# Generated by FakeRAM 2.0
VERSION 5.7 ;
BUSBITCHARS "[]" ;
PROPERTYDEFINITIONS
  MACRO width INTEGER ;
  MACRO depth INTEGER ;
  MACRO banks INTEGER ;
END PROPERTYDEFINITIONS
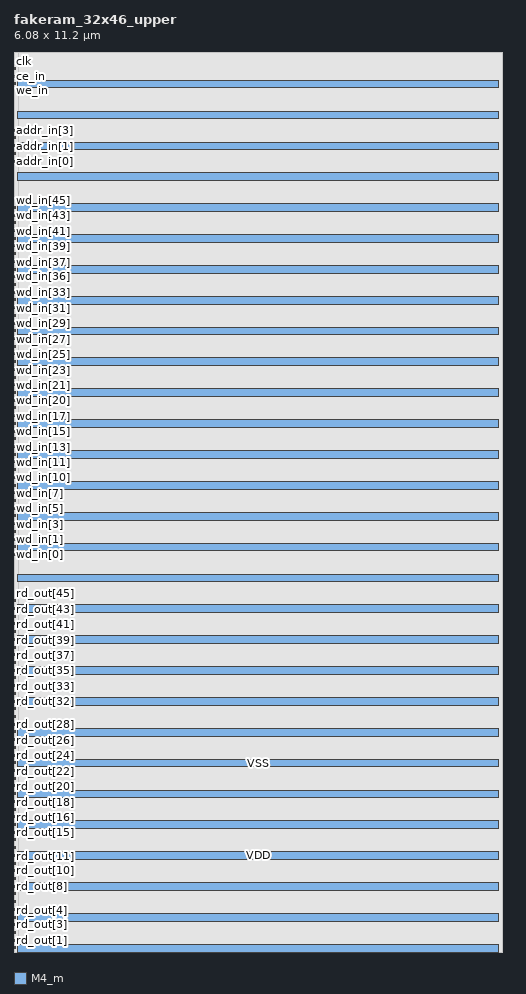
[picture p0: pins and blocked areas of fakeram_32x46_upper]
MACRO fakeram_32x46_upper
  PROPERTY width 46 ;
  PROPERTY depth 32 ;
  PROPERTY banks 1 ;
  FOREIGN fakeram_32x46_upper 0 0 ;
  SYMMETRY X Y R90 ;
  SIZE 6.080 BY 11.200 ;
  CLASS BLOCK ;
  PIN rd_out[0]
    DIRECTION OUTPUT ;
    USE SIGNAL ;
    SHAPE ABUTMENT ;
    PORT
      LAYER M4_m ;
      RECT 0.000 0.039 0.024 0.063 ;
    END
  END rd_out[0]
  PIN rd_out[1]
    DIRECTION OUTPUT ;
    USE SIGNAL ;
    SHAPE ABUTMENT ;
    PORT
      LAYER M4_m ;
      RECT 0.000 0.135 0.024 0.159 ;
    END
  END rd_out[1]
  PIN rd_out[2]
    DIRECTION OUTPUT ;
    USE SIGNAL ;
    SHAPE ABUTMENT ;
    PORT
      LAYER M4_m ;
      RECT 0.000 0.231 0.024 0.255 ;
    END
  END rd_out[2]
  PIN rd_out[3]
    DIRECTION OUTPUT ;
    USE SIGNAL ;
    SHAPE ABUTMENT ;
    PORT
      LAYER M4_m ;
      RECT 0.000 0.327 0.024 0.351 ;
    END
  END rd_out[3]
  PIN rd_out[4]
    DIRECTION OUTPUT ;
    USE SIGNAL ;
    SHAPE ABUTMENT ;
    PORT
      LAYER M4_m ;
      RECT 0.000 0.423 0.024 0.447 ;
    END
  END rd_out[4]
  PIN rd_out[5]
    DIRECTION OUTPUT ;
    USE SIGNAL ;
    SHAPE ABUTMENT ;
    PORT
      LAYER M4_m ;
      RECT 0.000 0.519 0.024 0.543 ;
    END
  END rd_out[5]
  PIN rd_out[6]
    DIRECTION OUTPUT ;
    USE SIGNAL ;
    SHAPE ABUTMENT ;
    PORT
      LAYER M4_m ;
      RECT 0.000 0.615 0.024 0.639 ;
    END
  END rd_out[6]
  PIN rd_out[7]
    DIRECTION OUTPUT ;
    USE SIGNAL ;
    SHAPE ABUTMENT ;
    PORT
      LAYER M4_m ;
      RECT 0.000 0.711 0.024 0.735 ;
    END
  END rd_out[7]
  PIN rd_out[8]
    DIRECTION OUTPUT ;
    USE SIGNAL ;
    SHAPE ABUTMENT ;
    PORT
      LAYER M4_m ;
      RECT 0.000 0.807 0.024 0.831 ;
    END
  END rd_out[8]
  PIN rd_out[9]
    DIRECTION OUTPUT ;
    USE SIGNAL ;
    SHAPE ABUTMENT ;
    PORT
      LAYER M4_m ;
      RECT 0.000 0.903 0.024 0.927 ;
    END
  END rd_out[9]
  PIN rd_out[10]
    DIRECTION OUTPUT ;
    USE SIGNAL ;
    SHAPE ABUTMENT ;
    PORT
      LAYER M4_m ;
      RECT 0.000 0.999 0.024 1.023 ;
    END
  END rd_out[10]
  PIN rd_out[11]
    DIRECTION OUTPUT ;
    USE SIGNAL ;
    SHAPE ABUTMENT ;
    PORT
      LAYER M4_m ;
      RECT 0.000 1.095 0.024 1.119 ;
    END
  END rd_out[11]
  PIN rd_out[12]
    DIRECTION OUTPUT ;
    USE SIGNAL ;
    SHAPE ABUTMENT ;
    PORT
      LAYER M4_m ;
      RECT 0.000 1.191 0.024 1.215 ;
    END
  END rd_out[12]
  PIN rd_out[13]
    DIRECTION OUTPUT ;
    USE SIGNAL ;
    SHAPE ABUTMENT ;
    PORT
      LAYER M4_m ;
      RECT 0.000 1.287 0.024 1.311 ;
    END
  END rd_out[13]
  PIN rd_out[14]
    DIRECTION OUTPUT ;
    USE SIGNAL ;
    SHAPE ABUTMENT ;
    PORT
      LAYER M4_m ;
      RECT 0.000 1.383 0.024 1.407 ;
    END
  END rd_out[14]
  PIN rd_out[15]
    DIRECTION OUTPUT ;
    USE SIGNAL ;
    SHAPE ABUTMENT ;
    PORT
      LAYER M4_m ;
      RECT 0.000 1.479 0.024 1.503 ;
    END
  END rd_out[15]
  PIN rd_out[16]
    DIRECTION OUTPUT ;
    USE SIGNAL ;
    SHAPE ABUTMENT ;
    PORT
      LAYER M4_m ;
      RECT 0.000 1.575 0.024 1.599 ;
    END
  END rd_out[16]
  PIN rd_out[17]
    DIRECTION OUTPUT ;
    USE SIGNAL ;
    SHAPE ABUTMENT ;
    PORT
      LAYER M4_m ;
      RECT 0.000 1.671 0.024 1.695 ;
    END
  END rd_out[17]
  PIN rd_out[18]
    DIRECTION OUTPUT ;
    USE SIGNAL ;
    SHAPE ABUTMENT ;
    PORT
      LAYER M4_m ;
      RECT 0.000 1.767 0.024 1.791 ;
    END
  END rd_out[18]
  PIN rd_out[19]
    DIRECTION OUTPUT ;
    USE SIGNAL ;
    SHAPE ABUTMENT ;
    PORT
      LAYER M4_m ;
      RECT 0.000 1.863 0.024 1.887 ;
    END
  END rd_out[19]
  PIN rd_out[20]
    DIRECTION OUTPUT ;
    USE SIGNAL ;
    SHAPE ABUTMENT ;
    PORT
      LAYER M4_m ;
      RECT 0.000 1.959 0.024 1.983 ;
    END
  END rd_out[20]
  PIN rd_out[21]
    DIRECTION OUTPUT ;
    USE SIGNAL ;
    SHAPE ABUTMENT ;
    PORT
      LAYER M4_m ;
      RECT 0.000 2.055 0.024 2.079 ;
    END
  END rd_out[21]
  PIN rd_out[22]
    DIRECTION OUTPUT ;
    USE SIGNAL ;
    SHAPE ABUTMENT ;
    PORT
      LAYER M4_m ;
      RECT 0.000 2.151 0.024 2.175 ;
    END
  END rd_out[22]
  PIN rd_out[23]
    DIRECTION OUTPUT ;
    USE SIGNAL ;
    SHAPE ABUTMENT ;
    PORT
      LAYER M4_m ;
      RECT 0.000 2.247 0.024 2.271 ;
    END
  END rd_out[23]
  PIN rd_out[24]
    DIRECTION OUTPUT ;
    USE SIGNAL ;
    SHAPE ABUTMENT ;
    PORT
      LAYER M4_m ;
      RECT 0.000 2.343 0.024 2.367 ;
    END
  END rd_out[24]
  PIN rd_out[25]
    DIRECTION OUTPUT ;
    USE SIGNAL ;
    SHAPE ABUTMENT ;
    PORT
      LAYER M4_m ;
      RECT 0.000 2.439 0.024 2.463 ;
    END
  END rd_out[25]
  PIN rd_out[26]
    DIRECTION OUTPUT ;
    USE SIGNAL ;
    SHAPE ABUTMENT ;
    PORT
      LAYER M4_m ;
      RECT 0.000 2.535 0.024 2.559 ;
    END
  END rd_out[26]
  PIN rd_out[27]
    DIRECTION OUTPUT ;
    USE SIGNAL ;
    SHAPE ABUTMENT ;
    PORT
      LAYER M4_m ;
      RECT 0.000 2.631 0.024 2.655 ;
    END
  END rd_out[27]
  PIN rd_out[28]
    DIRECTION OUTPUT ;
    USE SIGNAL ;
    SHAPE ABUTMENT ;
    PORT
      LAYER M4_m ;
      RECT 0.000 2.727 0.024 2.751 ;
    END
  END rd_out[28]
  PIN rd_out[29]
    DIRECTION OUTPUT ;
    USE SIGNAL ;
    SHAPE ABUTMENT ;
    PORT
      LAYER M4_m ;
      RECT 0.000 2.823 0.024 2.847 ;
    END
  END rd_out[29]
  PIN rd_out[30]
    DIRECTION OUTPUT ;
    USE SIGNAL ;
    SHAPE ABUTMENT ;
    PORT
      LAYER M4_m ;
      RECT 0.000 2.919 0.024 2.943 ;
    END
  END rd_out[30]
  PIN rd_out[31]
    DIRECTION OUTPUT ;
    USE SIGNAL ;
    SHAPE ABUTMENT ;
    PORT
      LAYER M4_m ;
      RECT 0.000 3.015 0.024 3.039 ;
    END
  END rd_out[31]
  PIN rd_out[32]
    DIRECTION OUTPUT ;
    USE SIGNAL ;
    SHAPE ABUTMENT ;
    PORT
      LAYER M4_m ;
      RECT 0.000 3.111 0.024 3.135 ;
    END
  END rd_out[32]
  PIN rd_out[33]
    DIRECTION OUTPUT ;
    USE SIGNAL ;
    SHAPE ABUTMENT ;
    PORT
      LAYER M4_m ;
      RECT 0.000 3.207 0.024 3.231 ;
    END
  END rd_out[33]
  PIN rd_out[34]
    DIRECTION OUTPUT ;
    USE SIGNAL ;
    SHAPE ABUTMENT ;
    PORT
      LAYER M4_m ;
      RECT 0.000 3.303 0.024 3.327 ;
    END
  END rd_out[34]
  PIN rd_out[35]
    DIRECTION OUTPUT ;
    USE SIGNAL ;
    SHAPE ABUTMENT ;
    PORT
      LAYER M4_m ;
      RECT 0.000 3.399 0.024 3.423 ;
    END
  END rd_out[35]
  PIN rd_out[36]
    DIRECTION OUTPUT ;
    USE SIGNAL ;
    SHAPE ABUTMENT ;
    PORT
      LAYER M4_m ;
      RECT 0.000 3.495 0.024 3.519 ;
    END
  END rd_out[36]
  PIN rd_out[37]
    DIRECTION OUTPUT ;
    USE SIGNAL ;
    SHAPE ABUTMENT ;
    PORT
      LAYER M4_m ;
      RECT 0.000 3.591 0.024 3.615 ;
    END
  END rd_out[37]
  PIN rd_out[38]
    DIRECTION OUTPUT ;
    USE SIGNAL ;
    SHAPE ABUTMENT ;
    PORT
      LAYER M4_m ;
      RECT 0.000 3.687 0.024 3.711 ;
    END
  END rd_out[38]
  PIN rd_out[39]
    DIRECTION OUTPUT ;
    USE SIGNAL ;
    SHAPE ABUTMENT ;
    PORT
      LAYER M4_m ;
      RECT 0.000 3.783 0.024 3.807 ;
    END
  END rd_out[39]
  PIN rd_out[40]
    DIRECTION OUTPUT ;
    USE SIGNAL ;
    SHAPE ABUTMENT ;
    PORT
      LAYER M4_m ;
      RECT 0.000 3.879 0.024 3.903 ;
    END
  END rd_out[40]
  PIN rd_out[41]
    DIRECTION OUTPUT ;
    USE SIGNAL ;
    SHAPE ABUTMENT ;
    PORT
      LAYER M4_m ;
      RECT 0.000 3.975 0.024 3.999 ;
    END
  END rd_out[41]
  PIN rd_out[42]
    DIRECTION OUTPUT ;
    USE SIGNAL ;
    SHAPE ABUTMENT ;
    PORT
      LAYER M4_m ;
      RECT 0.000 4.071 0.024 4.095 ;
    END
  END rd_out[42]
  PIN rd_out[43]
    DIRECTION OUTPUT ;
    USE SIGNAL ;
    SHAPE ABUTMENT ;
    PORT
      LAYER M4_m ;
      RECT 0.000 4.167 0.024 4.191 ;
    END
  END rd_out[43]
  PIN rd_out[44]
    DIRECTION OUTPUT ;
    USE SIGNAL ;
    SHAPE ABUTMENT ;
    PORT
      LAYER M4_m ;
      RECT 0.000 4.263 0.024 4.287 ;
    END
  END rd_out[44]
  PIN rd_out[45]
    DIRECTION OUTPUT ;
    USE SIGNAL ;
    SHAPE ABUTMENT ;
    PORT
      LAYER M4_m ;
      RECT 0.000 4.359 0.024 4.383 ;
    END
  END rd_out[45]
  PIN wd_in[0]
    DIRECTION INPUT ;
    USE SIGNAL ;
    SHAPE ABUTMENT ;
    PORT
      LAYER M4_m ;
      RECT 0.000 4.935 0.024 4.959 ;
    END
  END wd_in[0]
  PIN wd_in[1]
    DIRECTION INPUT ;
    USE SIGNAL ;
    SHAPE ABUTMENT ;
    PORT
      LAYER M4_m ;
      RECT 0.000 5.031 0.024 5.055 ;
    END
  END wd_in[1]
  PIN wd_in[2]
    DIRECTION INPUT ;
    USE SIGNAL ;
    SHAPE ABUTMENT ;
    PORT
      LAYER M4_m ;
      RECT 0.000 5.127 0.024 5.151 ;
    END
  END wd_in[2]
  PIN wd_in[3]
    DIRECTION INPUT ;
    USE SIGNAL ;
    SHAPE ABUTMENT ;
    PORT
      LAYER M4_m ;
      RECT 0.000 5.223 0.024 5.247 ;
    END
  END wd_in[3]
  PIN wd_in[4]
    DIRECTION INPUT ;
    USE SIGNAL ;
    SHAPE ABUTMENT ;
    PORT
      LAYER M4_m ;
      RECT 0.000 5.319 0.024 5.343 ;
    END
  END wd_in[4]
  PIN wd_in[5]
    DIRECTION INPUT ;
    USE SIGNAL ;
    SHAPE ABUTMENT ;
    PORT
      LAYER M4_m ;
      RECT 0.000 5.415 0.024 5.439 ;
    END
  END wd_in[5]
  PIN wd_in[6]
    DIRECTION INPUT ;
    USE SIGNAL ;
    SHAPE ABUTMENT ;
    PORT
      LAYER M4_m ;
      RECT 0.000 5.511 0.024 5.535 ;
    END
  END wd_in[6]
  PIN wd_in[7]
    DIRECTION INPUT ;
    USE SIGNAL ;
    SHAPE ABUTMENT ;
    PORT
      LAYER M4_m ;
      RECT 0.000 5.607 0.024 5.631 ;
    END
  END wd_in[7]
  PIN wd_in[8]
    DIRECTION INPUT ;
    USE SIGNAL ;
    SHAPE ABUTMENT ;
    PORT
      LAYER M4_m ;
      RECT 0.000 5.703 0.024 5.727 ;
    END
  END wd_in[8]
  PIN wd_in[9]
    DIRECTION INPUT ;
    USE SIGNAL ;
    SHAPE ABUTMENT ;
    PORT
      LAYER M4_m ;
      RECT 0.000 5.799 0.024 5.823 ;
    END
  END wd_in[9]
  PIN wd_in[10]
    DIRECTION INPUT ;
    USE SIGNAL ;
    SHAPE ABUTMENT ;
    PORT
      LAYER M4_m ;
      RECT 0.000 5.895 0.024 5.919 ;
    END
  END wd_in[10]
  PIN wd_in[11]
    DIRECTION INPUT ;
    USE SIGNAL ;
    SHAPE ABUTMENT ;
    PORT
      LAYER M4_m ;
      RECT 0.000 5.991 0.024 6.015 ;
    END
  END wd_in[11]
  PIN wd_in[12]
    DIRECTION INPUT ;
    USE SIGNAL ;
    SHAPE ABUTMENT ;
    PORT
      LAYER M4_m ;
      RECT 0.000 6.087 0.024 6.111 ;
    END
  END wd_in[12]
  PIN wd_in[13]
    DIRECTION INPUT ;
    USE SIGNAL ;
    SHAPE ABUTMENT ;
    PORT
      LAYER M4_m ;
      RECT 0.000 6.183 0.024 6.207 ;
    END
  END wd_in[13]
  PIN wd_in[14]
    DIRECTION INPUT ;
    USE SIGNAL ;
    SHAPE ABUTMENT ;
    PORT
      LAYER M4_m ;
      RECT 0.000 6.279 0.024 6.303 ;
    END
  END wd_in[14]
  PIN wd_in[15]
    DIRECTION INPUT ;
    USE SIGNAL ;
    SHAPE ABUTMENT ;
    PORT
      LAYER M4_m ;
      RECT 0.000 6.375 0.024 6.399 ;
    END
  END wd_in[15]
  PIN wd_in[16]
    DIRECTION INPUT ;
    USE SIGNAL ;
    SHAPE ABUTMENT ;
    PORT
      LAYER M4_m ;
      RECT 0.000 6.471 0.024 6.495 ;
    END
  END wd_in[16]
  PIN wd_in[17]
    DIRECTION INPUT ;
    USE SIGNAL ;
    SHAPE ABUTMENT ;
    PORT
      LAYER M4_m ;
      RECT 0.000 6.567 0.024 6.591 ;
    END
  END wd_in[17]
  PIN wd_in[18]
    DIRECTION INPUT ;
    USE SIGNAL ;
    SHAPE ABUTMENT ;
    PORT
      LAYER M4_m ;
      RECT 0.000 6.663 0.024 6.687 ;
    END
  END wd_in[18]
  PIN wd_in[19]
    DIRECTION INPUT ;
    USE SIGNAL ;
    SHAPE ABUTMENT ;
    PORT
      LAYER M4_m ;
      RECT 0.000 6.759 0.024 6.783 ;
    END
  END wd_in[19]
  PIN wd_in[20]
    DIRECTION INPUT ;
    USE SIGNAL ;
    SHAPE ABUTMENT ;
    PORT
      LAYER M4_m ;
      RECT 0.000 6.855 0.024 6.879 ;
    END
  END wd_in[20]
  PIN wd_in[21]
    DIRECTION INPUT ;
    USE SIGNAL ;
    SHAPE ABUTMENT ;
    PORT
      LAYER M4_m ;
      RECT 0.000 6.951 0.024 6.975 ;
    END
  END wd_in[21]
  PIN wd_in[22]
    DIRECTION INPUT ;
    USE SIGNAL ;
    SHAPE ABUTMENT ;
    PORT
      LAYER M4_m ;
      RECT 0.000 7.047 0.024 7.071 ;
    END
  END wd_in[22]
  PIN wd_in[23]
    DIRECTION INPUT ;
    USE SIGNAL ;
    SHAPE ABUTMENT ;
    PORT
      LAYER M4_m ;
      RECT 0.000 7.143 0.024 7.167 ;
    END
  END wd_in[23]
  PIN wd_in[24]
    DIRECTION INPUT ;
    USE SIGNAL ;
    SHAPE ABUTMENT ;
    PORT
      LAYER M4_m ;
      RECT 0.000 7.239 0.024 7.263 ;
    END
  END wd_in[24]
  PIN wd_in[25]
    DIRECTION INPUT ;
    USE SIGNAL ;
    SHAPE ABUTMENT ;
    PORT
      LAYER M4_m ;
      RECT 0.000 7.335 0.024 7.359 ;
    END
  END wd_in[25]
  PIN wd_in[26]
    DIRECTION INPUT ;
    USE SIGNAL ;
    SHAPE ABUTMENT ;
    PORT
      LAYER M4_m ;
      RECT 0.000 7.431 0.024 7.455 ;
    END
  END wd_in[26]
  PIN wd_in[27]
    DIRECTION INPUT ;
    USE SIGNAL ;
    SHAPE ABUTMENT ;
    PORT
      LAYER M4_m ;
      RECT 0.000 7.527 0.024 7.551 ;
    END
  END wd_in[27]
  PIN wd_in[28]
    DIRECTION INPUT ;
    USE SIGNAL ;
    SHAPE ABUTMENT ;
    PORT
      LAYER M4_m ;
      RECT 0.000 7.623 0.024 7.647 ;
    END
  END wd_in[28]
  PIN wd_in[29]
    DIRECTION INPUT ;
    USE SIGNAL ;
    SHAPE ABUTMENT ;
    PORT
      LAYER M4_m ;
      RECT 0.000 7.719 0.024 7.743 ;
    END
  END wd_in[29]
  PIN wd_in[30]
    DIRECTION INPUT ;
    USE SIGNAL ;
    SHAPE ABUTMENT ;
    PORT
      LAYER M4_m ;
      RECT 0.000 7.815 0.024 7.839 ;
    END
  END wd_in[30]
  PIN wd_in[31]
    DIRECTION INPUT ;
    USE SIGNAL ;
    SHAPE ABUTMENT ;
    PORT
      LAYER M4_m ;
      RECT 0.000 7.911 0.024 7.935 ;
    END
  END wd_in[31]
  PIN wd_in[32]
    DIRECTION INPUT ;
    USE SIGNAL ;
    SHAPE ABUTMENT ;
    PORT
      LAYER M4_m ;
      RECT 0.000 8.007 0.024 8.031 ;
    END
  END wd_in[32]
  PIN wd_in[33]
    DIRECTION INPUT ;
    USE SIGNAL ;
    SHAPE ABUTMENT ;
    PORT
      LAYER M4_m ;
      RECT 0.000 8.103 0.024 8.127 ;
    END
  END wd_in[33]
  PIN wd_in[34]
    DIRECTION INPUT ;
    USE SIGNAL ;
    SHAPE ABUTMENT ;
    PORT
      LAYER M4_m ;
      RECT 0.000 8.199 0.024 8.223 ;
    END
  END wd_in[34]
  PIN wd_in[35]
    DIRECTION INPUT ;
    USE SIGNAL ;
    SHAPE ABUTMENT ;
    PORT
      LAYER M4_m ;
      RECT 0.000 8.295 0.024 8.319 ;
    END
  END wd_in[35]
  PIN wd_in[36]
    DIRECTION INPUT ;
    USE SIGNAL ;
    SHAPE ABUTMENT ;
    PORT
      LAYER M4_m ;
      RECT 0.000 8.391 0.024 8.415 ;
    END
  END wd_in[36]
  PIN wd_in[37]
    DIRECTION INPUT ;
    USE SIGNAL ;
    SHAPE ABUTMENT ;
    PORT
      LAYER M4_m ;
      RECT 0.000 8.487 0.024 8.511 ;
    END
  END wd_in[37]
  PIN wd_in[38]
    DIRECTION INPUT ;
    USE SIGNAL ;
    SHAPE ABUTMENT ;
    PORT
      LAYER M4_m ;
      RECT 0.000 8.583 0.024 8.607 ;
    END
  END wd_in[38]
  PIN wd_in[39]
    DIRECTION INPUT ;
    USE SIGNAL ;
    SHAPE ABUTMENT ;
    PORT
      LAYER M4_m ;
      RECT 0.000 8.679 0.024 8.703 ;
    END
  END wd_in[39]
  PIN wd_in[40]
    DIRECTION INPUT ;
    USE SIGNAL ;
    SHAPE ABUTMENT ;
    PORT
      LAYER M4_m ;
      RECT 0.000 8.775 0.024 8.799 ;
    END
  END wd_in[40]
  PIN wd_in[41]
    DIRECTION INPUT ;
    USE SIGNAL ;
    SHAPE ABUTMENT ;
    PORT
      LAYER M4_m ;
      RECT 0.000 8.871 0.024 8.895 ;
    END
  END wd_in[41]
  PIN wd_in[42]
    DIRECTION INPUT ;
    USE SIGNAL ;
    SHAPE ABUTMENT ;
    PORT
      LAYER M4_m ;
      RECT 0.000 8.967 0.024 8.991 ;
    END
  END wd_in[42]
  PIN wd_in[43]
    DIRECTION INPUT ;
    USE SIGNAL ;
    SHAPE ABUTMENT ;
    PORT
      LAYER M4_m ;
      RECT 0.000 9.063 0.024 9.087 ;
    END
  END wd_in[43]
  PIN wd_in[44]
    DIRECTION INPUT ;
    USE SIGNAL ;
    SHAPE ABUTMENT ;
    PORT
      LAYER M4_m ;
      RECT 0.000 9.159 0.024 9.183 ;
    END
  END wd_in[44]
  PIN wd_in[45]
    DIRECTION INPUT ;
    USE SIGNAL ;
    SHAPE ABUTMENT ;
    PORT
      LAYER M4_m ;
      RECT 0.000 9.255 0.024 9.279 ;
    END
  END wd_in[45]
  PIN addr_in[0]
    DIRECTION INPUT ;
    USE SIGNAL ;
    SHAPE ABUTMENT ;
    PORT
      LAYER M4_m ;
      RECT 0.000 9.831 0.024 9.855 ;
    END
  END addr_in[0]
  PIN addr_in[1]
    DIRECTION INPUT ;
    USE SIGNAL ;
    SHAPE ABUTMENT ;
    PORT
      LAYER M4_m ;
      RECT 0.000 9.927 0.024 9.951 ;
    END
  END addr_in[1]
  PIN addr_in[2]
    DIRECTION INPUT ;
    USE SIGNAL ;
    SHAPE ABUTMENT ;
    PORT
      LAYER M4_m ;
      RECT 0.000 10.023 0.024 10.047 ;
    END
  END addr_in[2]
  PIN addr_in[3]
    DIRECTION INPUT ;
    USE SIGNAL ;
    SHAPE ABUTMENT ;
    PORT
      LAYER M4_m ;
      RECT 0.000 10.119 0.024 10.143 ;
    END
  END addr_in[3]
  PIN addr_in[4]
    DIRECTION INPUT ;
    USE SIGNAL ;
    SHAPE ABUTMENT ;
    PORT
      LAYER M4_m ;
      RECT 0.000 10.215 0.024 10.239 ;
    END
  END addr_in[4]
  PIN we_in
    DIRECTION INPUT ;
    USE SIGNAL ;
    SHAPE ABUTMENT ;
    PORT
      LAYER M4_m ;
      RECT 0.000 10.791 0.024 10.815 ;
    END
  END we_in
  PIN ce_in
    DIRECTION INPUT ;
    USE SIGNAL ;
    SHAPE ABUTMENT ;
    PORT
      LAYER M4_m ;
      RECT 0.000 10.887 0.024 10.911 ;
    END
  END ce_in
  PIN clk
    DIRECTION INPUT ;
    USE SIGNAL ;
    SHAPE ABUTMENT ;
    PORT
      LAYER M4_m ;
      RECT 0.000 10.983 0.024 11.007 ;
    END
  END clk
  PIN VSS
    DIRECTION INOUT ;
    USE GROUND ;
    PORT
      LAYER M4_m ;
      RECT 0.048 0.000 6.032 0.096 ;
      RECT 0.048 0.768 6.032 0.864 ;
      RECT 0.048 1.536 6.032 1.632 ;
      RECT 0.048 2.304 6.032 2.400 ;
      RECT 0.048 3.072 6.032 3.168 ;
      RECT 0.048 3.840 6.032 3.936 ;
      RECT 0.048 4.608 6.032 4.704 ;
      RECT 0.048 5.376 6.032 5.472 ;
      RECT 0.048 6.144 6.032 6.240 ;
      RECT 0.048 6.912 6.032 7.008 ;
      RECT 0.048 7.680 6.032 7.776 ;
      RECT 0.048 8.448 6.032 8.544 ;
      RECT 0.048 9.216 6.032 9.312 ;
      RECT 0.048 9.984 6.032 10.080 ;
      RECT 0.048 10.752 6.032 10.848 ;
    END
  END VSS
  PIN VDD
    DIRECTION INOUT ;
    USE POWER ;
    PORT
      LAYER M4_m ;
      RECT 0.048 0.384 6.032 0.480 ;
      RECT 0.048 1.152 6.032 1.248 ;
      RECT 0.048 1.920 6.032 2.016 ;
      RECT 0.048 2.688 6.032 2.784 ;
      RECT 0.048 3.456 6.032 3.552 ;
      RECT 0.048 4.224 6.032 4.320 ;
      RECT 0.048 4.992 6.032 5.088 ;
      RECT 0.048 5.760 6.032 5.856 ;
      RECT 0.048 6.528 6.032 6.624 ;
      RECT 0.048 7.296 6.032 7.392 ;
      RECT 0.048 8.064 6.032 8.160 ;
      RECT 0.048 8.832 6.032 8.928 ;
      RECT 0.048 9.600 6.032 9.696 ;
      RECT 0.048 10.368 6.032 10.464 ;
    END
  END VDD
  OBS
    LAYER M1_m ;
    RECT 0 0 6.080 11.200 ;
    LAYER M2_m ;
    RECT 0 0 6.080 11.200 ;
    LAYER M3_m ;
    RECT 0.059 0.000 6.080 11.200 ;
    LAYER M4_m ;
    RECT 0.059 0.000 6.080 11.200 ;
  END
END fakeram_32x46_upper

END LIBRARY
